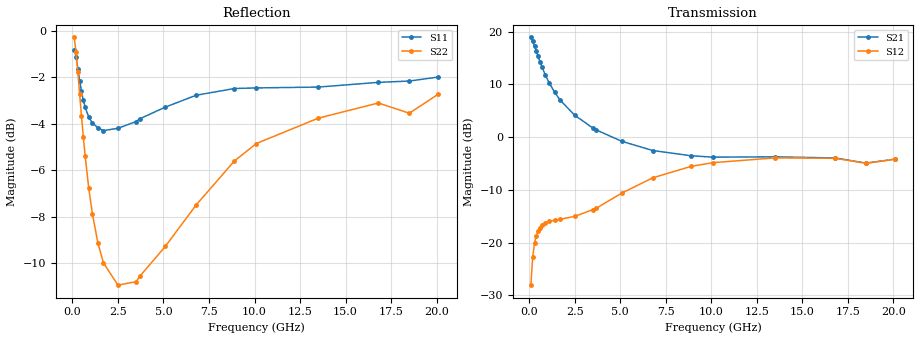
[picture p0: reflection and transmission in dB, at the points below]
!  Infineon Technologies AG
! BFR380L3 , PF131585-7, No.6, Th 09.10.01, soldered on pcb-board, measured with PP GSG850
!  Vce=0.75 V,  Ic=2.5 mA
! Common Emitter S-Parameters:  15. November 2001
#  GHz  S  MA  R  50
! f  S11  S21  S12  S22
! GHz  Mag  Ang  Mag  Ang  Mag  Ang  Mag  Ang
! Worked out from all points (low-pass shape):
!   201 points, 100 MHz to 20.1 GHz, reference 50 ohm
!   highest |S21| = 18.91 dB at 100 MHz (marker M1); lowest = -4.9 dB at 18.5 GHz (marker M2)
!   |S21| within 3 dB of the highest: start of sweep to 438.5 MHz
!   lowest |S11| = -4.3 dB at 1.7 GHz (marker M3), VSWR 4.13, Z = 12.3 - j5.15 ohm
!   |S11| at or under -10 dB: nowhere
!   |S22| runs from -11.1 to -0.3 dB; largest |S21 - S12| = 8.8
!   S11 on the Smith chart (normalised r, x): 100 MHz: 1.09, -4.62; 400 MHz: 0.30, -1.17; 1.1 GHz: 0.25, -0.32; 3.7 GHz: 0.23, +0.28; 8.9 GHz: 0.30, +1.05; 20.1 GHz: 0.96, +2.57
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0.1  0.9117 -23.2  8.816 164.7  0.03948 76.8  0.9686 -14.0
0.2  0.88 -44.0  8.1 150.8  0.0728 65.6  0.9013 -26.6
0.3  0.8289 -63.1  7.313 138.9  0.09863 56.1  0.8153 -37.0
0.4  0.7799 -78.9  6.525 129.0  0.1166 48.8  0.73 -45.4
0.5  0.7413 -92.6  5.812 120.8  0.1294 43.3  0.6551 -52.2
0.6  0.7094 -104.2  5.187 114.0  0.1385 39.1  0.5915 -57.6
0.7  0.6849 -113.9  4.669 108.1  0.1452 35.7  0.5381 -62.1
0.9  0.6518 -129.7  3.855 98.6  0.1532 31.4  0.4577 -69.2
1.1  0.6334 -142.2  3.279 90.9  0.1586 28.8  0.4034 -74.9
1.4  0.6184 -156.4  2.667 81.5  0.1629 27.2  0.3492 -81.6
1.7  0.6098 -167.5  2.251 73.6  0.1664 27.2  0.3165 -87.7
2.5  0.6168 170.6  1.614 56.5  0.1768 30.8  0.2832 -102.7
3.5  0.6378 150.4  1.22 39.9  0.2053 38.1  0.2881 -122.0
3.7  0.6465 147.6  1.167 37.3  0.212 38.9  0.2959 -126.4
5.1  0.6851 125.6  0.9113 20.9  0.295 41.6  0.3431 -153.2
6.8  0.7269 104.4  0.7452 8.6  0.4115 34.5  0.4218 175.4
8.9  0.7515 84.8  0.665 -0.4  0.5276 19.9  0.5247 145.5
10.1  0.7537 75.8  0.6452 -4.6  0.5722 11.0  0.5719 130.1
13.5  0.7569 58.3  0.6497 -18.9  0.6347 -11.4  0.6486 97.4
16.8  0.7748 47.0  0.6343 -31.1  0.6292 -27.4  0.6994 75.3
18.5  0.7799 45.1  0.5663 -39.2  0.5641 -35.8  0.6648 69.8
20.1  0.7956 38.2  0.6173 -43.2  0.6162 -40.6  0.7311 59.1
